VERSION 5.7 ;
  NOWIREEXTENSIONATPIN ON ;
  DIVIDERCHAR "/" ;
  BUSBITCHARS "[]" ;
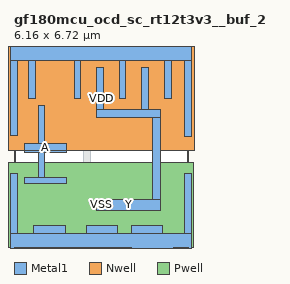
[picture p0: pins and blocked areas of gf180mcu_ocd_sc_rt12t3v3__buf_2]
MACRO gf180mcu_ocd_sc_rt12t3v3__buf_2
  CLASS CORE ;
  FOREIGN gf180mcu_ocd_sc_rt12t3v3__buf_2 ;
  ORIGIN 0.000 0.000 ;
  SIZE 6.160 BY 6.720 ;
  SYMMETRY X Y ;
  SITE unithd ;
  PIN A
    DIRECTION INPUT ;
    USE SIGNAL ;
    ANTENNAGATEAREA 1.672300 ;
    PORT
      LAYER Metal1 ;
        RECT 0.865 3.490 1.095 4.825 ;
        RECT 0.370 3.160 1.870 3.490 ;
        RECT 0.865 2.285 1.095 3.160 ;
        RECT 0.370 2.055 1.870 2.285 ;
    END
  END A
  PIN Y
    DIRECTION OUTPUT ;
    USE SIGNAL ;
    ANTENNADIFFAREA 1.953800 ;
    PORT
      LAYER Metal1 ;
        RECT 2.925 4.670 3.155 6.180 ;
        RECT 4.525 4.670 4.755 6.180 ;
        RECT 2.925 4.410 5.170 4.670 ;
        RECT 4.910 1.500 5.170 4.410 ;
        RECT 2.930 1.120 5.170 1.500 ;
    END
  END Y
  PIN VDD
    DIRECTION INOUT ;
    USE POWER ;
    SHAPE ABUTMENT ;
    PORT
      LAYER Nwell ;
        RECT -0.610 3.245 6.770 7.330 ;
        RECT -0.610 3.240 4.110 3.245 ;
      LAYER Metal1 ;
        RECT -0.115 6.420 6.275 7.020 ;
        RECT -0.115 3.750 0.115 6.420 ;
        RECT 0.525 5.060 0.755 6.420 ;
        RECT 2.125 5.060 2.355 6.420 ;
        RECT 3.725 5.060 3.955 6.420 ;
        RECT 5.325 5.065 5.555 6.420 ;
        RECT 6.045 3.745 6.275 6.420 ;
    END
  END VDD
  PIN VSS
    DIRECTION INOUT ;
    USE GROUND ;
    SHAPE ABUTMENT ;
    PORT
      LAYER Pwell ;
        RECT -0.180 -0.180 6.340 2.815 ;
        RECT 0.000 -0.300 4.160 -0.180 ;
        RECT 5.655 -0.300 6.160 -0.180 ;
      LAYER Metal1 ;
        RECT -0.115 0.300 0.115 2.410 ;
        RECT 0.700 0.300 1.810 0.585 ;
        RECT 2.550 0.300 3.660 0.585 ;
        RECT 4.155 0.300 5.265 0.585 ;
        RECT 6.045 0.300 6.275 2.410 ;
        RECT -0.115 -0.300 6.275 0.300 ;
    END
  END VSS
  OBS
      LAYER Metal1 ;
        RECT 1.325 4.670 1.555 6.180 ;
        RECT 2.465 4.670 2.695 4.825 ;
        RECT 1.325 4.410 2.695 4.670 ;
        RECT 2.465 2.285 2.695 4.410 ;
        RECT 2.360 2.055 4.575 2.285 ;
        RECT 1.080 1.380 1.460 1.500 ;
        RECT 2.360 1.380 2.620 2.055 ;
        RECT 1.080 1.120 2.620 1.380 ;
  END
END gf180mcu_ocd_sc_rt12t3v3__buf_2
END LIBRARY

